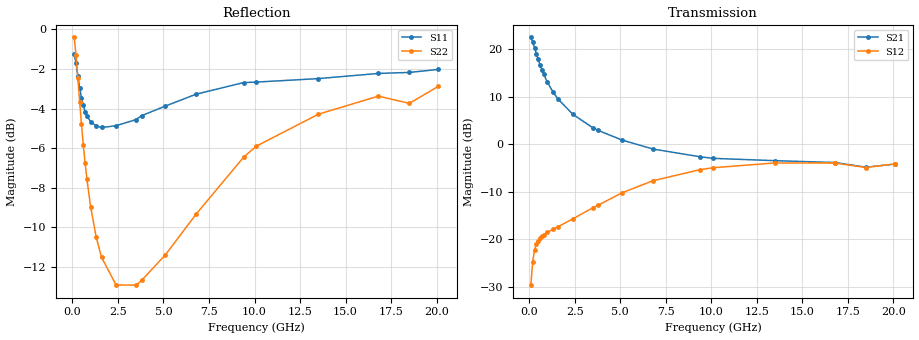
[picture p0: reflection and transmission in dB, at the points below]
!  Infineon Technologies AG
! BFR380L3 , PF131585-7, No.6, Th 09.10.01, soldered on pcb-board, measured with PP GSG850
!  Vce=1.5 V,  Ic=4.0 mA
! Common Emitter S-Parameters:  15. November 2001
#  GHz  S  MA  R  50
! f  S11  S21  S12  S22
! GHz  Mag  Ang  Mag  Ang  Mag  Ang  Mag  Ang
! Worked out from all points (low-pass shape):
!   201 points, 100 MHz to 20.1 GHz, reference 50 ohm
!   highest |S21| = 22.49 dB at 100 MHz (marker M1); lowest = -4.8 dB at 18.5 GHz (marker M2)
!   |S21| within 3 dB of the highest: start of sweep to 367.1 MHz
!   lowest |S11| = -5.0 dB at 1.6 GHz (marker M3), VSWR 3.60, Z = 14 - j4.02 ohm
!   |S11| at or under -10 dB: nowhere
!   |S22| runs from -13.1 to -0.4 dB; largest |S21 - S12| = 13
!   S11 on the Smith chart (normalised r, x): 100 MHz: 1.20, -3.79; 400 MHz: 0.33, -0.96; 1 GHz: 0.29, -0.29; 3.8 GHz: 0.27, +0.31; 9.4 GHz: 0.35, +1.09; 20.1 GHz: 0.98, +2.57
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0.1  0.8656 -27.1  13.32 162.0  0.03301 73.9  0.9547 -16.7
0.2  0.822 -51.5  11.88 146.5  0.05846 63.2  0.8613 -31.0
0.3  0.7631 -72.5  10.38 134.0  0.07675 54.4  0.7527 -42.2
0.4  0.7112 -89.2  8.992 124.1  0.08879 48.1  0.6555 -50.6
0.5  0.6715 -102.9  7.823 116.3  0.09704 43.8  0.5753 -57.1
0.6  0.6424 -114.3  6.871 110.1  0.1034 41.1  0.5112 -62.1
0.7  0.6191 -123.8  6.11 104.8  0.108 39.2  0.4592 -66.1
0.8  0.6043 -131.8  5.477 100.3  0.1119 38.1  0.4177 -69.5
1  0.5846 -144.7  4.531 92.9  0.1184 37.1  0.3568 -74.9
1.3  0.5707 -159.1  3.59 84.0  0.1272 37.5  0.2997 -81.4
1.6  0.5652 -170.0  2.979 76.7  0.1362 38.9  0.2656 -87.0
2.4  0.571 168.7  2.071 60.9  0.1641 43.2  0.2261 -101.2
3.5  0.592 147.6  1.493 43.7  0.2148 46.5  0.2259 -121.2
3.8  0.6055 143.2  1.399 39.8  0.229 46.6  0.2322 -128.1
5.1  0.64 124.4  1.109 24.3  0.3086 43.9  0.2692 -151.9
6.8  0.6862 104.6  0.8918 9.7  0.4134 35.3  0.3417 177.6
9.400001  0.7339 82.0  0.7387 -4.4  0.5415 17.6  0.4754 142.1
10.1  0.7361 76.8  0.7115 -7.3  0.5667 12.7  0.507 133.6
13.5  0.7511 59.0  0.6724 -20.9  0.6364 -9.8  0.6104 100.4
16.8  0.7741 47.2  0.6433 -32.2  0.6346 -26.2  0.6783 77.4
18.5  0.7786 45.2  0.5737 -40.0  0.5695 -34.7  0.6504 71.5
20.1  0.7923 38.1  0.6201 -43.6  0.6226 -39.8  0.7183 60.6
